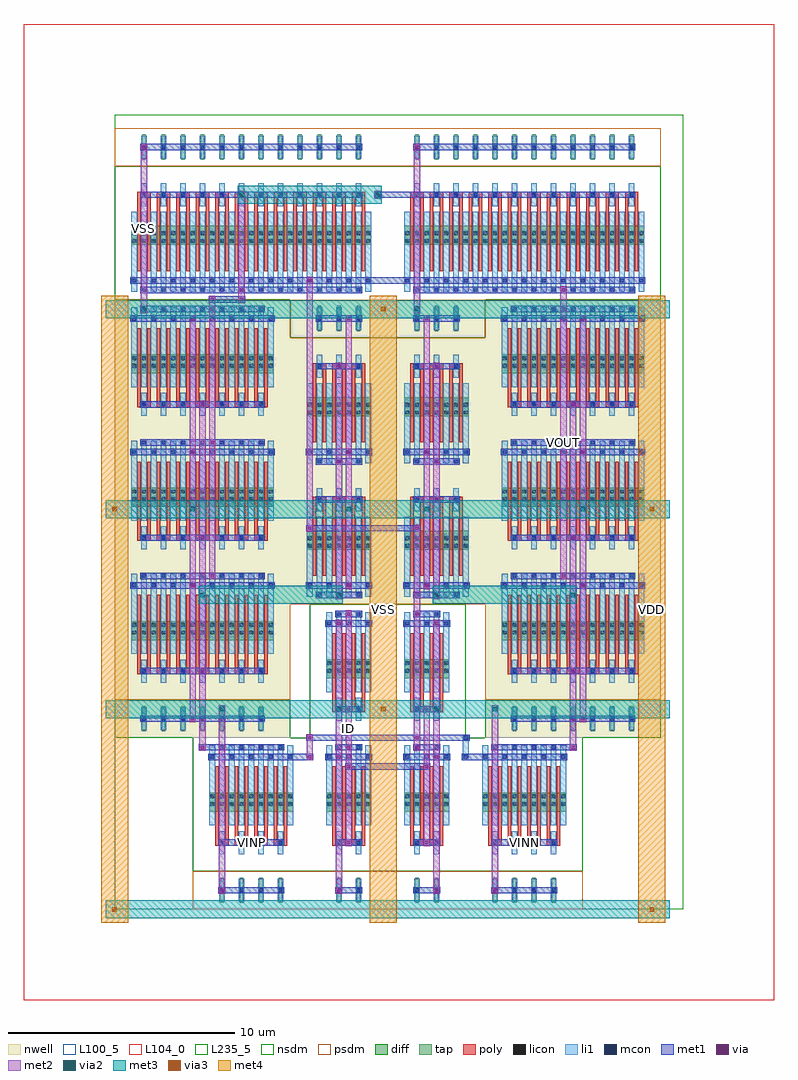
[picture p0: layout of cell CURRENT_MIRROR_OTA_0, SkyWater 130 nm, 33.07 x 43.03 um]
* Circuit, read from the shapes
.subckt CURRENT_MIRROR_OTA_0 ID VDD VINN VINP VOUT VSS
XM1 n1 n1 n2 VSS sky130_fd_pr__nfet_01v8 w=0.84 l=0.15 m=24
XM2 n3 VINP n2 VSS sky130_fd_pr__nfet_01v8 w=0.84 l=0.15 m=8
XM3 ID ID VSS VSS sky130_fd_pr__nfet_01v8 w=0.84 l=0.15 m=8
XM4 n2 ID VSS VSS sky130_fd_pr__nfet_01v8 w=0.84 l=0.15 m=8
XM5 VOUT n1 n2 VSS sky130_fd_pr__nfet_01v8 w=0.84 l=0.15 m=24
XM6 n4 VINN n2 VSS sky130_fd_pr__nfet_01v8 w=0.84 l=0.15 m=8
XM7 n1 n3 VDD VDD sky130_fd_pr__pfet_01v8 w=0.84 l=0.15 m=42
XM8 n3 n3 VDD VDD sky130_fd_pr__pfet_01v8 w=0.84 l=0.15 m=12
XM9 n4 n4 VDD VDD sky130_fd_pr__pfet_01v8 w=0.84 l=0.15 m=12
XM10 VOUT n4 VDD VDD sky130_fd_pr__pfet_01v8 w=0.84 l=0.15 m=42
.ends

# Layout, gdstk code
from math import pi, radians
import gdstk
lib = gdstk.Library(unit=1e-6, precision=1e-09)
def R(c, l, rs):  # rectangles x0, y0, x1, y1
    for r in rs: c.add(gdstk.rectangle(r[:2], r[2:], *l))
def A(c, l, x, y, w, h, nx, ny, dx, dy):  # array of equal rectangles
    R(c, l, [(x+i*dx, y+j*dy, x+i*dx+w, y+j*dy+h) for i in range(nx) for j in range(ny)])
def P(c, l, *ps):  # polygons
    for p in ps: c.add(gdstk.Polygon(p, *l))
nwell = (64, 20)
diff = (65, 20)
tap = (65, 44)
poly = (66, 20)
licon = (66, 44)
li1 = (67, 20)
mcon = (67, 44)
met1 = (68, 20)
via = (68, 44)
met2 = (69, 20)
via2 = (69, 44)
met3 = (70, 20)
via3 = (70, 44)
met4 = (71, 20)
nsdm = (93, 44)
psdm = (94, 20)
L100_5 = (100, 5)
L104_0 = (104, 0)
L235_5 = (235, 5)

dcl_nmos_s_47956387_x2_y = lib.new_cell('DCL_NMOS_S_47956387_X2_Y2_1725376080')
R(dcl_nmos_s_47956387_x2_y, diff, [(0.735,2.415,2.705,3.255), (0.735,8.295,2.705,9.135)])
R(dcl_nmos_s_47956387_x2_y, tap, [(1.205,12.04,1.375,13.16), (2.065,12.04,2.235,13.16)])
A(dcl_nmos_s_47956387_x2_y, poly, 1, 1.26, 0.15, 3.36, 4, 2, 0.43, 5.88)
R(dcl_nmos_s_47956387_x2_y, poly, [(1,4.485,1.58,4.755), (1.86,4.485,2.44,4.755), (1,10.365,1.58,10.635), (1.86,10.365,2.44,10.635)])
A(dcl_nmos_s_47956387_x2_y, licon, 0.775, 2.495, 0.17, 0.17, 3, 2, 0.43, 0.34)
A(dcl_nmos_s_47956387_x2_y, licon, 1.635, 2.495, 0.17, 0.17, 3, 2, 0.43, 0.34)
A(dcl_nmos_s_47956387_x2_y, licon, 0.775, 8.375, 0.17, 0.17, 3, 2, 0.43, 0.34)
A(dcl_nmos_s_47956387_x2_y, licon, 1.635, 8.375, 0.17, 0.17, 3, 2, 0.43, 0.34)
R(dcl_nmos_s_47956387_x2_y, licon, [(1.205,4.535,1.375,4.705), (2.065,4.535,2.235,4.705), (1.205,10.415,1.375,10.585), (2.065,10.415,2.235,10.585), (1.205,12.515,1.375,12.685), (1.205,12.515,1.375,12.685), (2.065,12.515,2.235,12.685), (2.065,12.515,2.235,12.685)])
A(dcl_nmos_s_47956387_x2_y, li1, 0.735, 0.335, 0.25, 3.53, 5, 2, 0.43, 5.88)
R(dcl_nmos_s_47956387_x2_y, li1, [(1.165,4.115,1.415,5.125), (2.025,4.115,2.275,5.125), (1.165,9.995,1.415,11.005), (2.025,9.995,2.275,11.005), (1.165,12.095,1.415,13.105), (2.025,12.095,2.275,13.105)])
A(dcl_nmos_s_47956387_x2_y, mcon, 0.775, 0.755, 0.17, 0.17, 3, 2, 0.86, 5.88)
R(dcl_nmos_s_47956387_x2_y, mcon, [(1.205,0.335,1.375,0.505), (2.065,0.335,2.235,0.505), (1.205,4.535,1.375,4.705), (2.065,4.535,2.235,4.705), (1.205,6.215,1.375,6.385), (2.065,6.215,2.235,6.385), (1.205,10.415,1.375,10.585), (2.065,10.415,2.235,10.585), (1.205,12.515,1.375,12.685), (2.065,12.515,2.235,12.685)])
R(dcl_nmos_s_47956387_x2_y, met1, [(1.12,0.28,2.32,0.56), (0.69,0.7,2.75,0.98), (1.12,4.48,2.32,4.76), (1.12,6.16,2.32,6.44), (0.69,6.58,2.75,6.86), (1.12,10.36,2.32,10.64), (1.12,12.46,2.32,12.74)])
A(dcl_nmos_s_47956387_x2_y, via, 2.075, 0.765, 0.15, 0.15, 1, 3, 0, 5.88)
R(dcl_nmos_s_47956387_x2_y, via, [(1.645,0.345,1.795,0.495), (1.645,4.545,1.795,4.695), (1.645,6.225,1.795,6.375), (1.645,10.425,1.795,10.575)])
R(dcl_nmos_s_47956387_x2_y, met2, [(1.58,0.26,1.86,10.66), (2.01,0.68,2.29,12.76)])
R(dcl_nmos_s_47956387_x2_y, nsdm, [(0,0,3.44,11.76)])
R(dcl_nmos_s_47956387_x2_y, psdm, [(0,11.76,3.44,13.44)])
R(dcl_nmos_s_47956387_x2_y, L100_5, [(0,0,3.44,13.44)])

dcl_pmos_s_40212493_x3_y = lib.new_cell('DCL_PMOS_S_40212493_X3_Y2_1725376081')
R(dcl_pmos_s_40212493_x3_y, nwell, [(0,0,4.3,13.44)])
R(dcl_pmos_s_40212493_x3_y, diff, [(0.735,2.415,3.565,3.255), (0.735,8.295,3.565,9.135)])
A(dcl_pmos_s_40212493_x3_y, tap, 1.205, 12.04, 0.17, 1.12, 3, 1, 0.86, 0)
A(dcl_pmos_s_40212493_x3_y, poly, 1, 1.26, 0.15, 3.36, 6, 2, 0.43, 5.88)
A(dcl_pmos_s_40212493_x3_y, poly, 1, 4.485, 0.58, 0.27, 3, 2, 0.86, 5.88)
A(dcl_pmos_s_40212493_x3_y, licon, 0.775, 2.495, 0.17, 0.17, 3, 2, 0.43, 0.34)
A(dcl_pmos_s_40212493_x3_y, licon, 1.635, 2.495, 0.17, 0.17, 3, 2, 0.43, 0.34)
A(dcl_pmos_s_40212493_x3_y, licon, 2.495, 2.495, 0.17, 0.17, 3, 2, 0.43, 0.34)
A(dcl_pmos_s_40212493_x3_y, licon, 1.205, 4.535, 0.17, 0.17, 3, 2, 0.86, 5.88)
A(dcl_pmos_s_40212493_x3_y, licon, 0.775, 8.375, 0.17, 0.17, 3, 2, 0.43, 0.34)
A(dcl_pmos_s_40212493_x3_y, licon, 1.635, 8.375, 0.17, 0.17, 3, 2, 0.43, 0.34)
A(dcl_pmos_s_40212493_x3_y, licon, 2.495, 8.375, 0.17, 0.17, 3, 2, 0.43, 0.34)
R(dcl_pmos_s_40212493_x3_y, licon, [(1.205,12.515,1.375,12.685), (1.205,12.515,1.375,12.685), (2.065,12.515,2.235,12.685), (2.065,12.515,2.235,12.685), (2.925,12.515,3.095,12.685), (2.925,12.515,3.095,12.685)])
A(dcl_pmos_s_40212493_x3_y, li1, 0.735, 0.335, 0.25, 3.53, 7, 2, 0.43, 5.88)
A(dcl_pmos_s_40212493_x3_y, li1, 1.165, 4.115, 0.25, 1.01, 3, 2, 0.86, 5.88)
A(dcl_pmos_s_40212493_x3_y, li1, 1.165, 12.095, 0.25, 1.01, 3, 1, 0.86, 0)
A(dcl_pmos_s_40212493_x3_y, mcon, 1.205, 0.335, 0.17, 0.17, 3, 2, 0.86, 4.2)
A(dcl_pmos_s_40212493_x3_y, mcon, 0.775, 0.755, 0.17, 0.17, 4, 2, 0.86, 5.88)
A(dcl_pmos_s_40212493_x3_y, mcon, 1.205, 6.215, 0.17, 0.17, 3, 2, 0.86, 4.2)
A(dcl_pmos_s_40212493_x3_y, mcon, 1.205, 12.515, 0.17, 0.17, 3, 1, 0.86, 0)
R(dcl_pmos_s_40212493_x3_y, met1, [(1.12,0.28,3.18,0.56), (0.69,0.7,3.61,0.98), (1.12,4.48,3.18,4.76), (1.12,6.16,3.18,6.44), (0.69,6.58,3.61,6.86), (1.12,10.36,3.18,10.64), (1.12,12.46,3.18,12.74)])
A(dcl_pmos_s_40212493_x3_y, via, 2.505, 0.765, 0.15, 0.15, 1, 3, 0, 5.88)
R(dcl_pmos_s_40212493_x3_y, via, [(2.075,0.345,2.225,0.495), (2.075,4.545,2.225,4.695), (2.075,6.225,2.225,6.375), (2.075,10.425,2.225,10.575)])
R(dcl_pmos_s_40212493_x3_y, met2, [(2.01,0.26,2.29,10.66), (2.44,0.68,2.72,12.76)])
R(dcl_pmos_s_40212493_x3_y, nsdm, [(0,11.76,4.3,13.44)])
R(dcl_pmos_s_40212493_x3_y, psdm, [(0,0,4.3,11.76)])
R(dcl_pmos_s_40212493_x3_y, L100_5, [(0,0,4.3,13.44)])

nmos_s_18635307_x2_y2_17 = lib.new_cell('NMOS_S_18635307_X2_Y2_1725376084')
R(nmos_s_18635307_x2_y2_17, diff, [(0.735,2.415,2.705,3.255), (0.735,8.295,2.705,9.135)])
R(nmos_s_18635307_x2_y2_17, tap, [(1.205,12.04,1.375,13.16), (2.065,12.04,2.235,13.16)])
A(nmos_s_18635307_x2_y2_17, poly, 1, 1.26, 0.15, 3.36, 4, 2, 0.43, 5.88)
R(nmos_s_18635307_x2_y2_17, poly, [(1,4.485,1.58,4.755), (1.86,4.485,2.44,4.755), (1,10.365,1.58,10.635), (1.86,10.365,2.44,10.635)])
A(nmos_s_18635307_x2_y2_17, licon, 0.775, 2.495, 0.17, 0.17, 3, 2, 0.43, 0.34)
A(nmos_s_18635307_x2_y2_17, licon, 1.635, 2.495, 0.17, 0.17, 3, 2, 0.43, 0.34)
A(nmos_s_18635307_x2_y2_17, licon, 0.775, 8.375, 0.17, 0.17, 3, 2, 0.43, 0.34)
A(nmos_s_18635307_x2_y2_17, licon, 1.635, 8.375, 0.17, 0.17, 3, 2, 0.43, 0.34)
R(nmos_s_18635307_x2_y2_17, licon, [(1.205,4.535,1.375,4.705), (2.065,4.535,2.235,4.705), (1.205,10.415,1.375,10.585), (2.065,10.415,2.235,10.585), (1.205,12.515,1.375,12.685), (1.205,12.515,1.375,12.685), (2.065,12.515,2.235,12.685), (2.065,12.515,2.235,12.685)])
A(nmos_s_18635307_x2_y2_17, li1, 0.735, 0.335, 0.25, 3.53, 5, 2, 0.43, 5.88)
R(nmos_s_18635307_x2_y2_17, li1, [(1.165,4.115,1.415,5.125), (2.025,4.115,2.275,5.125), (1.165,9.995,1.415,11.005), (2.025,9.995,2.275,11.005), (1.165,12.095,1.415,13.105), (2.025,12.095,2.275,13.105)])
A(nmos_s_18635307_x2_y2_17, mcon, 0.775, 0.755, 0.17, 0.17, 3, 2, 0.86, 5.88)
R(nmos_s_18635307_x2_y2_17, mcon, [(1.205,0.335,1.375,0.505), (2.065,0.335,2.235,0.505), (1.205,4.535,1.375,4.705), (2.065,4.535,2.235,4.705), (1.205,6.215,1.375,6.385), (2.065,6.215,2.235,6.385), (1.205,10.415,1.375,10.585), (2.065,10.415,2.235,10.585), (1.205,12.515,1.375,12.685), (2.065,12.515,2.235,12.685)])
R(nmos_s_18635307_x2_y2_17, met1, [(1.12,0.28,2.32,0.56), (0.69,0.7,2.75,0.98), (1.12,4.48,2.32,4.76), (1.12,6.16,2.32,6.44), (0.69,6.58,2.75,6.86), (1.12,10.36,2.32,10.64), (1.12,12.46,2.32,12.74)])
A(nmos_s_18635307_x2_y2_17, via, 2.075, 0.765, 0.15, 0.15, 1, 3, 0, 5.88)
R(nmos_s_18635307_x2_y2_17, via, [(1.215,0.345,1.365,0.495), (1.645,4.545,1.795,4.695), (1.215,6.225,1.365,6.375), (1.645,10.425,1.795,10.575)])
R(nmos_s_18635307_x2_y2_17, met2, [(1.15,0.26,1.43,6.46), (2.01,0.68,2.29,12.76), (1.58,4.46,1.86,10.66)])
R(nmos_s_18635307_x2_y2_17, nsdm, [(0,0,3.44,11.76)])
R(nmos_s_18635307_x2_y2_17, psdm, [(0,11.76,3.44,13.44)])
R(nmos_s_18635307_x2_y2_17, L100_5, [(0,0,3.44,13.44)])

pmos_s_18257507_x7_y3_17 = lib.new_cell('PMOS_S_18257507_X7_Y3_1725376085')
R(pmos_s_18257507_x7_y3_17, nwell, [(0,0,7.74,19.32)])
A(pmos_s_18257507_x7_y3_17, diff, 0.735, 2.415, 6.27, 0.84, 1, 3, 0, 5.88)
A(pmos_s_18257507_x7_y3_17, tap, 1.205, 17.92, 0.17, 1.12, 7, 1, 0.86, 0)
A(pmos_s_18257507_x7_y3_17, poly, 1, 1.26, 0.15, 3.36, 14, 3, 0.43, 5.88)
A(pmos_s_18257507_x7_y3_17, poly, 1, 4.485, 0.58, 0.27, 7, 3, 0.86, 5.88)
A(pmos_s_18257507_x7_y3_17, licon, 0.775, 2.495, 0.17, 0.17, 3, 2, 0.43, 0.34)
A(pmos_s_18257507_x7_y3_17, licon, 1.635, 2.495, 0.17, 0.17, 3, 2, 0.43, 0.34)
A(pmos_s_18257507_x7_y3_17, licon, 2.495, 2.495, 0.17, 0.17, 3, 2, 0.43, 0.34)
A(pmos_s_18257507_x7_y3_17, licon, 3.355, 2.495, 0.17, 0.17, 3, 2, 0.43, 0.34)
A(pmos_s_18257507_x7_y3_17, licon, 4.215, 2.495, 0.17, 0.17, 3, 2, 0.43, 0.34)
A(pmos_s_18257507_x7_y3_17, licon, 5.075, 2.495, 0.17, 0.17, 3, 2, 0.43, 0.34)
A(pmos_s_18257507_x7_y3_17, licon, 5.935, 2.495, 0.17, 0.17, 3, 2, 0.43, 0.34)
A(pmos_s_18257507_x7_y3_17, licon, 1.205, 4.535, 0.17, 0.17, 7, 3, 0.86, 5.88)
A(pmos_s_18257507_x7_y3_17, licon, 0.775, 8.375, 0.17, 0.17, 3, 2, 0.43, 0.34)
A(pmos_s_18257507_x7_y3_17, licon, 1.635, 8.375, 0.17, 0.17, 3, 2, 0.43, 0.34)
A(pmos_s_18257507_x7_y3_17, licon, 2.495, 8.375, 0.17, 0.17, 3, 2, 0.43, 0.34)
A(pmos_s_18257507_x7_y3_17, licon, 3.355, 8.375, 0.17, 0.17, 3, 2, 0.43, 0.34)
A(pmos_s_18257507_x7_y3_17, licon, 4.215, 8.375, 0.17, 0.17, 3, 2, 0.43, 0.34)
A(pmos_s_18257507_x7_y3_17, licon, 5.075, 8.375, 0.17, 0.17, 3, 2, 0.43, 0.34)
A(pmos_s_18257507_x7_y3_17, licon, 5.935, 8.375, 0.17, 0.17, 3, 2, 0.43, 0.34)
A(pmos_s_18257507_x7_y3_17, licon, 0.775, 14.255, 0.17, 0.17, 3, 2, 0.43, 0.34)
A(pmos_s_18257507_x7_y3_17, licon, 1.635, 14.255, 0.17, 0.17, 3, 2, 0.43, 0.34)
A(pmos_s_18257507_x7_y3_17, licon, 2.495, 14.255, 0.17, 0.17, 3, 2, 0.43, 0.34)
A(pmos_s_18257507_x7_y3_17, licon, 3.355, 14.255, 0.17, 0.17, 3, 2, 0.43, 0.34)
A(pmos_s_18257507_x7_y3_17, licon, 4.215, 14.255, 0.17, 0.17, 3, 2, 0.43, 0.34)
A(pmos_s_18257507_x7_y3_17, licon, 5.075, 14.255, 0.17, 0.17, 3, 2, 0.43, 0.34)
A(pmos_s_18257507_x7_y3_17, licon, 5.935, 14.255, 0.17, 0.17, 3, 2, 0.43, 0.34)
R(pmos_s_18257507_x7_y3_17, licon, [(1.205,18.395,1.375,18.565), (1.205,18.395,1.375,18.565), (1.205,18.395,1.375,18.565), (2.065,18.395,2.235,18.565), (2.065,18.395,2.235,18.565), (2.065,18.395,2.235,18.565), (2.925,18.395,3.095,18.565), (2.925,18.395,3.095,18.565), (2.925,18.395,3.095,18.565), (3.785,18.395,3.955,18.565), (3.785,18.395,3.955,18.565), (3.785,18.395,3.955,18.565), (4.645,18.395,4.815,18.565), (4.645,18.395,4.815,18.565), (4.645,18.395,4.815,18.565), (5.505,18.395,5.675,18.565), (5.505,18.395,5.675,18.565), (5.505,18.395,5.675,18.565), (6.365,18.395,6.535,18.565), (6.365,18.395,6.535,18.565), (6.365,18.395,6.535,18.565)])
A(pmos_s_18257507_x7_y3_17, li1, 0.735, 0.335, 0.25, 3.53, 15, 3, 0.43, 5.88)
A(pmos_s_18257507_x7_y3_17, li1, 1.165, 4.115, 0.25, 1.01, 7, 3, 0.86, 5.88)
A(pmos_s_18257507_x7_y3_17, li1, 1.165, 17.975, 0.25, 1.01, 7, 1, 0.86, 0)
A(pmos_s_18257507_x7_y3_17, mcon, 1.205, 0.335, 0.17, 0.17, 7, 2, 0.86, 4.2)
A(pmos_s_18257507_x7_y3_17, mcon, 0.775, 0.755, 0.17, 0.17, 8, 3, 0.86, 5.88)
A(pmos_s_18257507_x7_y3_17, mcon, 1.205, 6.215, 0.17, 0.17, 7, 2, 0.86, 4.2)
A(pmos_s_18257507_x7_y3_17, mcon, 1.205, 12.095, 0.17, 0.17, 7, 2, 0.86, 4.2)
A(pmos_s_18257507_x7_y3_17, mcon, 1.205, 18.395, 0.17, 0.17, 7, 1, 0.86, 0)
A(pmos_s_18257507_x7_y3_17, met1, 0.69, 0.7, 6.36, 0.28, 1, 3, 0, 5.88)
R(pmos_s_18257507_x7_y3_17, met1, [(1.12,0.28,6.62,0.56), (1.12,4.48,6.62,4.76), (1.12,6.16,6.62,6.44), (1.12,10.36,6.62,10.64), (1.12,12.04,6.62,12.32), (1.12,16.24,6.62,16.52), (1.12,18.34,6.62,18.62)])
A(pmos_s_18257507_x7_y3_17, via, 3.365, 0.345, 0.15, 0.15, 1, 3, 0, 5.88)
A(pmos_s_18257507_x7_y3_17, via, 4.225, 0.765, 0.15, 0.15, 1, 4, 0, 5.88)
A(pmos_s_18257507_x7_y3_17, via, 3.795, 4.545, 0.15, 0.15, 1, 3, 0, 5.88)
R(pmos_s_18257507_x7_y3_17, met2, [(3.3,0.26,3.58,12.34), (4.16,0.68,4.44,18.64), (3.73,4.46,4.01,16.54)])
R(pmos_s_18257507_x7_y3_17, nsdm, [(0,17.64,7.74,19.32)])
R(pmos_s_18257507_x7_y3_17, psdm, [(0,0,7.74,17.64)])
R(pmos_s_18257507_x7_y3_17, L100_5, [(0,0,7.74,19.32)])

dcl_nmos_10568373_x12_y1 = lib.new_cell('DCL_NMOS_10568373_X12_Y1_1725376079')
R(dcl_nmos_10568373_x12_y1, diff, [(0.735,2.415,11.305,3.255)])
A(dcl_nmos_10568373_x12_y1, tap, 1.205, 6.16, 0.17, 1.12, 12, 1, 0.86, 0)
A(dcl_nmos_10568373_x12_y1, poly, 1, 1.26, 0.15, 3.36, 24, 1, 0.43, 0)
A(dcl_nmos_10568373_x12_y1, poly, 1, 4.485, 0.58, 0.27, 12, 1, 0.86, 0)
A(dcl_nmos_10568373_x12_y1, licon, 0.775, 2.495, 0.17, 0.17, 3, 2, 0.43, 0.34)
A(dcl_nmos_10568373_x12_y1, licon, 1.635, 2.495, 0.17, 0.17, 3, 2, 0.43, 0.34)
A(dcl_nmos_10568373_x12_y1, licon, 2.495, 2.495, 0.17, 0.17, 3, 2, 0.43, 0.34)
A(dcl_nmos_10568373_x12_y1, licon, 3.355, 2.495, 0.17, 0.17, 3, 2, 0.43, 0.34)
A(dcl_nmos_10568373_x12_y1, licon, 4.215, 2.495, 0.17, 0.17, 3, 2, 0.43, 0.34)
A(dcl_nmos_10568373_x12_y1, licon, 5.075, 2.495, 0.17, 0.17, 3, 2, 0.43, 0.34)
A(dcl_nmos_10568373_x12_y1, licon, 5.935, 2.495, 0.17, 0.17, 3, 2, 0.43, 0.34)
A(dcl_nmos_10568373_x12_y1, licon, 6.795, 2.495, 0.17, 0.17, 3, 2, 0.43, 0.34)
A(dcl_nmos_10568373_x12_y1, licon, 7.655, 2.495, 0.17, 0.17, 3, 2, 0.43, 0.34)
A(dcl_nmos_10568373_x12_y1, licon, 8.515, 2.495, 0.17, 0.17, 3, 2, 0.43, 0.34)
A(dcl_nmos_10568373_x12_y1, licon, 9.375, 2.495, 0.17, 0.17, 3, 2, 0.43, 0.34)
A(dcl_nmos_10568373_x12_y1, licon, 10.235, 2.495, 0.17, 0.17, 3, 2, 0.43, 0.34)
A(dcl_nmos_10568373_x12_y1, licon, 1.205, 4.535, 0.17, 0.17, 12, 2, 0.86, 2.1)
A(dcl_nmos_10568373_x12_y1, li1, 0.735, 0.335, 0.25, 3.53, 25, 1, 0.43, 0)
A(dcl_nmos_10568373_x12_y1, li1, 1.165, 4.115, 0.25, 1.01, 12, 2, 0.86, 2.1)
A(dcl_nmos_10568373_x12_y1, mcon, 1.205, 0.335, 0.17, 0.17, 12, 2, 0.86, 4.2)
A(dcl_nmos_10568373_x12_y1, mcon, 0.775, 0.755, 0.17, 0.17, 13, 1, 0.86, 0)
A(dcl_nmos_10568373_x12_y1, mcon, 1.205, 6.635, 0.17, 0.17, 12, 1, 0.86, 0)
R(dcl_nmos_10568373_x12_y1, met1, [(1.12,0.28,10.92,0.56), (0.69,0.7,11.35,0.98), (1.12,4.48,10.92,4.76), (1.12,6.58,10.92,6.86)])
R(dcl_nmos_10568373_x12_y1, via, [(5.515,0.345,5.665,0.495), (5.515,4.545,5.665,4.695)])
R(dcl_nmos_10568373_x12_y1, met2, [(5.45,0.26,5.73,4.78)])
R(dcl_nmos_10568373_x12_y1, nsdm, [(0,0,12.04,5.88)])
R(dcl_nmos_10568373_x12_y1, psdm, [(0,5.88,12.04,7.56)])
R(dcl_nmos_10568373_x12_y1, L100_5, [(0,0,12.04,7.56)])

nmos_4t_40251920_x4_y1_1 = lib.new_cell('NMOS_4T_40251920_X4_Y1_1725376082')
R(nmos_4t_40251920_x4_y1_1, diff, [(0.735,2.415,4.425,3.255)])
A(nmos_4t_40251920_x4_y1_1, tap, 1.205, 6.16, 0.17, 1.12, 4, 1, 0.86, 0)
A(nmos_4t_40251920_x4_y1_1, poly, 1, 1.26, 0.15, 3.36, 8, 1, 0.43, 0)
A(nmos_4t_40251920_x4_y1_1, poly, 1, 4.485, 0.58, 0.27, 4, 1, 0.86, 0)
A(nmos_4t_40251920_x4_y1_1, licon, 0.775, 2.495, 0.17, 0.17, 3, 2, 0.43, 0.34)
A(nmos_4t_40251920_x4_y1_1, licon, 1.635, 2.495, 0.17, 0.17, 3, 2, 0.43, 0.34)
A(nmos_4t_40251920_x4_y1_1, licon, 2.495, 2.495, 0.17, 0.17, 3, 2, 0.43, 0.34)
A(nmos_4t_40251920_x4_y1_1, licon, 3.355, 2.495, 0.17, 0.17, 3, 2, 0.43, 0.34)
A(nmos_4t_40251920_x4_y1_1, licon, 1.205, 4.535, 0.17, 0.17, 4, 2, 0.86, 2.1)
A(nmos_4t_40251920_x4_y1_1, li1, 0.735, 0.335, 0.25, 3.53, 9, 1, 0.43, 0)
A(nmos_4t_40251920_x4_y1_1, li1, 1.165, 4.115, 0.25, 1.01, 4, 2, 0.86, 2.1)
A(nmos_4t_40251920_x4_y1_1, mcon, 1.205, 0.335, 0.17, 0.17, 4, 2, 0.86, 4.2)
A(nmos_4t_40251920_x4_y1_1, mcon, 0.775, 0.755, 0.17, 0.17, 5, 1, 0.86, 0)
A(nmos_4t_40251920_x4_y1_1, mcon, 1.205, 6.635, 0.17, 0.17, 4, 1, 0.86, 0)
R(nmos_4t_40251920_x4_y1_1, met1, [(1.12,0.28,4.04,0.56), (0.69,0.7,4.47,0.98), (1.12,4.48,4.04,4.76), (1.12,6.58,4.04,6.86)])
R(nmos_4t_40251920_x4_y1_1, nsdm, [(0,0,5.16,5.88)])
R(nmos_4t_40251920_x4_y1_1, psdm, [(0,5.88,5.16,7.56)])
R(nmos_4t_40251920_x4_y1_1, L100_5, [(0,0,5.16,7.56)])

nmos_4t_8992804_x12_y1_1 = lib.new_cell('NMOS_4T_8992804_X12_Y1_1725376083')
R(nmos_4t_8992804_x12_y1_1, diff, [(0.735,2.415,11.305,3.255)])
A(nmos_4t_8992804_x12_y1_1, tap, 1.205, 6.16, 0.17, 1.12, 12, 1, 0.86, 0)
A(nmos_4t_8992804_x12_y1_1, poly, 1, 1.26, 0.15, 3.36, 24, 1, 0.43, 0)
A(nmos_4t_8992804_x12_y1_1, poly, 1, 4.485, 0.58, 0.27, 12, 1, 0.86, 0)
A(nmos_4t_8992804_x12_y1_1, licon, 0.775, 2.495, 0.17, 0.17, 3, 2, 0.43, 0.34)
A(nmos_4t_8992804_x12_y1_1, licon, 1.635, 2.495, 0.17, 0.17, 3, 2, 0.43, 0.34)
A(nmos_4t_8992804_x12_y1_1, licon, 2.495, 2.495, 0.17, 0.17, 3, 2, 0.43, 0.34)
A(nmos_4t_8992804_x12_y1_1, licon, 3.355, 2.495, 0.17, 0.17, 3, 2, 0.43, 0.34)
A(nmos_4t_8992804_x12_y1_1, licon, 4.215, 2.495, 0.17, 0.17, 3, 2, 0.43, 0.34)
A(nmos_4t_8992804_x12_y1_1, licon, 5.075, 2.495, 0.17, 0.17, 3, 2, 0.43, 0.34)
A(nmos_4t_8992804_x12_y1_1, licon, 5.935, 2.495, 0.17, 0.17, 3, 2, 0.43, 0.34)
A(nmos_4t_8992804_x12_y1_1, licon, 6.795, 2.495, 0.17, 0.17, 3, 2, 0.43, 0.34)
A(nmos_4t_8992804_x12_y1_1, licon, 7.655, 2.495, 0.17, 0.17, 3, 2, 0.43, 0.34)
A(nmos_4t_8992804_x12_y1_1, licon, 8.515, 2.495, 0.17, 0.17, 3, 2, 0.43, 0.34)
A(nmos_4t_8992804_x12_y1_1, licon, 9.375, 2.495, 0.17, 0.17, 3, 2, 0.43, 0.34)
A(nmos_4t_8992804_x12_y1_1, licon, 10.235, 2.495, 0.17, 0.17, 3, 2, 0.43, 0.34)
A(nmos_4t_8992804_x12_y1_1, licon, 1.205, 4.535, 0.17, 0.17, 12, 2, 0.86, 2.1)
A(nmos_4t_8992804_x12_y1_1, li1, 0.735, 0.335, 0.25, 3.53, 25, 1, 0.43, 0)
A(nmos_4t_8992804_x12_y1_1, li1, 1.165, 4.115, 0.25, 1.01, 12, 2, 0.86, 2.1)
A(nmos_4t_8992804_x12_y1_1, mcon, 1.205, 0.335, 0.17, 0.17, 12, 2, 0.86, 4.2)
A(nmos_4t_8992804_x12_y1_1, mcon, 0.775, 0.755, 0.17, 0.17, 13, 1, 0.86, 0)
A(nmos_4t_8992804_x12_y1_1, mcon, 1.205, 6.635, 0.17, 0.17, 12, 1, 0.86, 0)
R(nmos_4t_8992804_x12_y1_1, met1, [(1.12,0.28,10.92,0.56), (0.69,0.7,11.35,0.98), (1.12,4.48,10.92,4.76), (1.12,6.58,10.92,6.86)])
R(nmos_4t_8992804_x12_y1_1, nsdm, [(0,0,12.04,5.88)])
R(nmos_4t_8992804_x12_y1_1, psdm, [(0,5.88,12.04,7.56)])
R(nmos_4t_8992804_x12_y1_1, L100_5, [(0,0,12.04,7.56)])

current_mirror_ota_0 = lib.new_cell('CURRENT_MIRROR_OTA_0')
R(current_mirror_ota_0, li1, [(15.355,6.635,15.605,6.805), (15.355,6.635,15.605,6.805), (15.355,6.635,15.605,6.805), (15.355,6.635,15.605,6.805), (15.355,6.635,15.605,6.805), (15.355,6.635,15.605,6.805), (15.355,6.72,15.605,7.56), (15.355,7.475,15.605,7.645), (15.355,7.475,15.605,7.645), (15.355,7.475,15.605,7.645), (15.355,7.475,15.605,7.645), (15.355,7.475,15.605,7.645), (15.355,7.475,15.605,7.645)])
R(current_mirror_ota_0, mcon, [(15.395,6.635,15.565,6.805), (15.395,6.635,15.565,6.805), (15.395,6.635,15.565,6.805), (15.395,6.635,15.565,6.805), (15.395,6.635,15.565,6.805), (15.395,6.635,15.565,6.805), (15.395,7.475,15.565,7.645), (15.395,7.475,15.565,7.645), (15.395,7.475,15.565,7.645), (15.395,7.475,15.565,7.645), (15.395,7.475,15.565,7.645), (15.395,7.475,15.565,7.645)])
R(current_mirror_ota_0, met1, [(4.57,0.7,4.89,0.98), (4.57,0.7,4.89,0.98), (4.57,0.7,4.89,0.98), (16.61,0.7,16.93,0.98), (16.61,0.7,16.93,0.98), (16.61,0.7,16.93,0.98), (16.61,0.7,16.93,0.98), (10.16,6.16,10.48,6.44), (10.16,6.16,10.48,6.44), (10.32,6.16,13.76,6.44), (13.6,6.16,13.92,6.44), (13.6,6.16,13.92,6.44), (7.74,6.58,8.6,6.86), (8.44,6.58,8.76,6.86), (8.44,6.58,8.76,6.86), (8.44,6.58,8.76,6.86), (8.44,6.58,8.76,6.86), (8.44,6.58,8.76,6.86), (8.44,6.58,8.76,6.86), (8.44,6.58,8.76,6.86), (8.44,6.58,8.76,6.86), (15.31,6.58,15.65,6.86), (15.31,6.58,15.65,6.86), (15.31,6.58,15.65,6.86), (15.31,6.58,15.65,6.86), (15.31,6.58,15.65,6.86), (15.31,6.58,15.65,6.86), (15.48,6.58,16.34,6.86), (3.71,7,4.03,7.28), (3.71,7,4.03,7.28), (3.71,7,4.03,7.28), (3.71,7,4.03,7.28), (3.87,7,4.73,7.28), (19.35,7,20.21,7.28), (20.05,7,20.37,7.28), (20.05,7,20.37,7.28), (20.05,7,20.37,7.28), (20.05,7,20.37,7.28), (8.44,7.42,8.76,7.7), (8.44,7.42,8.76,7.7), (8.44,7.42,8.76,7.7), (8.44,7.42,8.76,7.7), (8.44,7.42,8.76,7.7), (8.44,7.42,8.76,7.7), (8.44,7.42,8.76,7.7), (8.44,7.42,8.76,7.7), (8.6,7.42,13.33,7.7), (13.17,7.42,13.49,7.7), (13.17,7.42,13.49,7.7), (13.17,7.42,13.49,7.7), (13.17,7.42,13.49,7.7), (13.17,7.42,13.49,7.7), (13.17,7.42,13.49,7.7), (13.17,7.42,13.49,7.7), (13.17,7.42,13.49,7.7), (13.33,7.42,15.48,7.7), (15.31,7.42,15.65,7.7), (15.31,7.42,15.65,7.7), (15.31,7.42,15.65,7.7), (15.31,7.42,15.65,7.7), (15.31,7.42,15.65,7.7), (15.31,7.42,15.65,7.7), (8.44,16.66,8.76,16.94), (8.44,16.66,8.76,16.94), (8.44,16.66,8.76,16.94), (8.44,16.66,8.76,16.94), (8.6,16.66,13.33,16.94), (13.17,16.66,13.49,16.94), (13.17,16.66,13.49,16.94), (13.17,16.66,13.49,16.94), (13.17,16.66,13.49,16.94), (4.14,26.74,4.46,27.02), (4.14,26.74,4.46,27.02), (4.14,26.74,4.46,27.02), (4.14,26.74,4.46,27.02), (4.3,26.74,5.59,27.02), (5.43,26.74,5.75,27.02), (5.43,26.74,5.75,27.02), (5.43,26.74,5.75,27.02), (5.43,26.74,5.75,27.02), (19.62,27.16,19.94,27.44), (19.62,27.16,19.94,27.44), (8.44,27.58,8.76,27.86), (8.44,27.58,8.76,27.86), (8.44,27.58,8.76,27.86), (8.44,27.58,8.76,27.86), (11.18,27.58,12.9,27.86), (11.45,31.36,11.77,31.64), (11.61,31.36,13.33,31.64), (1.13,33.46,1.45,33.74), (1.13,33.46,1.45,33.74), (1.13,33.46,1.45,33.74), (1.13,33.46,1.45,33.74), (1.13,33.46,1.45,33.74), (13.17,33.46,13.49,33.74), (13.17,33.46,13.49,33.74)])
P(current_mirror_ota_0, met1, [(0,0),(0,0),(0,0),(0,0)],
  [(0,0),(0,0),(0,0),(0,0)],
  [(0,0),(0,0),(0,0),(0,0)],
  [(0,0),(0,0),(0,0),(0,0)],
  [(0,0),(0,0),(0,0),(0,0)],
  [(0,0),(0,0),(0,0),(0,0)],
  [(0,0),(0,0),(0,0),(0,0)],
  [(0,0),(0,0),(0,0),(0,0)],
  [(0,0),(0,0),(0,0),(0,0)],
  [(0,0),(0,0),(0,0),(0,0)],
  [(0,0),(0,0),(0,0),(0,0)],
  [(0,0),(0,0),(0,0),(0,0)],
  [(0,0),(0,0),(0,0),(0,0)],
  [(0,0),(0,0),(0,0),(0,0)],
  [(0,0),(0,0),(0,0),(0,0)],
  [(0,0),(0,0),(0,0),(0,0)])
R(current_mirror_ota_0, via, [(4.655,0.765,4.805,0.915), (4.655,0.765,4.805,0.915), (4.655,0.765,4.805,0.915), (16.695,0.765,16.845,0.915), (16.695,0.765,16.845,0.915), (16.695,0.765,16.845,0.915), (16.695,0.765,16.845,0.915), (10.245,6.225,10.395,6.375), (10.245,6.225,10.395,6.375), (13.685,6.225,13.835,6.375), (13.685,6.225,13.835,6.375), (8.525,6.645,8.675,6.795), (8.525,6.645,8.675,6.795), (8.525,6.645,8.675,6.795), (8.525,6.645,8.675,6.795), (8.525,6.645,8.675,6.795), (8.525,6.645,8.675,6.795), (8.525,6.645,8.675,6.795), (8.525,6.645,8.675,6.795), (3.795,7.065,3.945,7.215), (3.795,7.065,3.945,7.215), (3.795,7.065,3.945,7.215), (3.795,7.065,3.945,7.215), (20.135,7.065,20.285,7.215), (20.135,7.065,20.285,7.215), (20.135,7.065,20.285,7.215), (20.135,7.065,20.285,7.215), (8.525,7.485,8.675,7.635), (8.525,7.485,8.675,7.635), (8.525,7.485,8.675,7.635), (8.525,7.485,8.675,7.635), (8.525,7.485,8.675,7.635), (8.525,7.485,8.675,7.635), (8.525,7.485,8.675,7.635), (8.525,7.485,8.675,7.635), (13.255,7.485,13.405,7.635), (13.255,7.485,13.405,7.635), (13.255,7.485,13.405,7.635), (13.255,7.485,13.405,7.635), (13.255,7.485,13.405,7.635), (13.255,7.485,13.405,7.635), (13.255,7.485,13.405,7.635), (13.255,7.485,13.405,7.635), (8.525,16.725,8.675,16.875), (8.525,16.725,8.675,16.875), (8.525,16.725,8.675,16.875), (8.525,16.725,8.675,16.875), (13.255,16.725,13.405,16.875), (13.255,16.725,13.405,16.875), (13.255,16.725,13.405,16.875), (13.255,16.725,13.405,16.875), (4.225,26.805,4.375,26.955), (4.225,26.805,4.375,26.955), (4.225,26.805,4.375,26.955), (4.225,26.805,4.375,26.955), (5.515,26.805,5.665,26.955), (5.515,26.805,5.665,26.955), (5.515,26.805,5.665,26.955), (5.515,26.805,5.665,26.955), (19.705,27.225,19.855,27.375), (19.705,27.225,19.855,27.375), (8.525,27.645,8.675,27.795), (8.525,27.645,8.675,27.795), (8.525,27.645,8.675,27.795), (8.525,27.645,8.675,27.795), (11.535,31.425,11.685,31.575), (1.215,33.525,1.365,33.675), (1.215,33.525,1.365,33.675), (1.215,33.525,1.365,33.675), (1.215,33.525,1.365,33.675), (1.215,33.525,1.365,33.675), (13.255,33.525,13.405,33.675), (13.255,33.525,13.405,33.675)])
R(current_mirror_ota_0, met2, [(4.59,0.68,4.87,1), (4.59,0.68,4.87,1), (4.59,0.68,4.87,1), (16.63,0.68,16.91,1), (16.63,0.68,16.91,1), (16.63,0.68,16.91,1), (16.63,0.68,16.91,1), (4.59,0.84,4.87,8.82), (16.63,0.84,16.91,8.82), (10.18,6.14,10.46,6.46), (10.18,6.14,10.46,6.46), (13.62,6.14,13.9,6.46), (13.62,6.14,13.9,6.46), (8.46,6.56,8.74,6.88), (8.46,6.56,8.74,6.88), (8.46,6.56,8.74,6.88), (8.46,6.56,8.74,6.88), (8.46,6.56,8.74,6.88), (8.46,6.56,8.74,6.88), (8.46,6.56,8.74,6.88), (8.46,6.56,8.74,6.88), (8.46,6.72,8.74,7.56), (3.73,6.98,4.01,7.3), (3.73,6.98,4.01,7.3), (3.73,6.98,4.01,7.3), (3.73,6.98,4.01,7.3), (20.07,6.98,20.35,7.3), (20.07,6.98,20.35,7.3), (20.07,6.98,20.35,7.3), (20.07,6.98,20.35,7.3), (3.73,7.14,4.01,10.5), (20.07,7.14,20.35,10.5), (8.46,7.4,8.74,7.72), (8.46,7.4,8.74,7.72), (8.46,7.4,8.74,7.72), (8.46,7.4,8.74,7.72), (8.46,7.4,8.74,7.72), (8.46,7.4,8.74,7.72), (8.46,7.4,8.74,7.72), (8.46,7.4,8.74,7.72), (13.19,7.4,13.47,7.72), (13.19,7.4,13.47,7.72), (13.19,7.4,13.47,7.72), (13.19,7.4,13.47,7.72), (13.19,7.4,13.47,7.72), (13.19,7.4,13.47,7.72), (13.19,7.4,13.47,7.72), (13.19,7.4,13.47,7.72), (4.59,8.635,4.87,9.005), (4.59,8.635,4.87,9.005), (4.59,8.635,4.87,9.005), (9.75,8.635,10.03,9.005), (9.75,8.635,10.03,9.005), (9.75,8.635,10.03,9.005), (9.75,8.635,10.03,9.005), (9.75,8.635,10.03,9.005), (9.75,8.635,10.03,9.005), (9.75,8.635,10.03,9.005), (14.05,8.635,14.33,9.005), (14.05,8.635,14.33,9.005), (14.05,8.635,14.33,9.005), (14.05,8.635,14.33,9.005), (14.05,8.635,14.33,9.005), (14.05,8.635,14.33,9.005), (16.63,8.635,16.91,9.005), (16.63,8.635,16.91,9.005), (16.63,8.635,16.91,9.005), (16.63,8.635,16.91,9.005), (13.19,13.02,13.47,16.8), (3.73,13.675,4.01,14.045), (3.73,13.675,4.01,14.045), (9.75,13.675,10.03,14.045), (9.75,13.675,10.03,14.045), (14.05,13.675,14.33,14.045), (14.05,13.675,14.33,14.045), (20.07,13.675,20.35,14.045), (20.07,13.675,20.35,14.045), (8.46,16.64,8.74,16.96), (8.46,16.64,8.74,16.96), (8.46,16.64,8.74,16.96), (8.46,16.64,8.74,16.96), (13.19,16.64,13.47,16.96), (13.19,16.64,13.47,16.96), (13.19,16.64,13.47,16.96), (13.19,16.64,13.47,16.96), (8.46,16.8,8.74,27.72), (3.3,17.455,3.58,17.825), (3.3,17.455,3.58,17.825), (3.3,17.455,3.58,17.825), (10.18,17.455,10.46,17.825), (10.18,17.455,10.46,17.825), (10.18,17.455,10.46,17.825), (10.18,17.455,10.46,17.825), (13.62,17.455,13.9,17.825), (13.62,17.455,13.9,17.825), (13.62,17.455,13.9,17.825), (13.62,17.455,13.9,17.825), (13.62,17.455,13.9,17.825), (20.5,17.455,20.78,17.825), (20.5,17.455,20.78,17.825), (1.15,26.275,1.43,26.645), (1.15,26.275,1.43,26.645), (1.15,26.275,1.43,26.645), (1.15,26.275,1.43,26.645), (1.15,26.275,1.43,26.645), (13.19,26.275,13.47,26.645), (13.19,26.275,13.47,26.645), (1.15,26.46,1.43,33.6), (4.16,26.46,4.44,26.88), (13.19,26.46,13.47,33.6), (19.64,26.46,19.92,27.3), (4.16,26.72,4.44,27.04), (4.16,26.72,4.44,27.04), (4.16,26.72,4.44,27.04), (4.16,26.72,4.44,27.04), (5.45,26.72,5.73,27.04), (5.45,26.72,5.73,27.04), (5.45,26.72,5.73,27.04), (5.45,26.72,5.73,27.04), (5.45,26.88,5.73,27.3), (19.64,27.14,19.92,27.46), (19.64,27.14,19.92,27.46), (8.46,27.56,8.74,27.88), (8.46,27.56,8.74,27.88), (8.46,27.56,8.74,27.88), (8.46,27.56,8.74,27.88), (5.45,31.315,5.73,31.685), (5.45,31.315,5.73,31.685), (11.47,31.315,11.75,31.685), (11.47,31.34,11.75,31.66), (11.47,31.379,11.75,31.621), (1.15,33.44,1.43,33.76), (1.15,33.44,1.43,33.76), (1.15,33.44,1.43,33.76), (1.15,33.44,1.43,33.76), (1.15,33.44,1.43,33.76), (13.19,33.44,13.47,33.76), (13.19,33.44,13.47,33.76)])
P(current_mirror_ota_0, met2, [(0,0),(0,0),(0,0),(0,0)],
  [(0,0),(0,0),(0,0),(0,0)],
  [(0,0),(0,0),(0,0),(0,0)],
  [(0,0),(0,0),(0,0),(0,0)],
  [(0,0),(0,0),(0,0),(0,0)],
  [(0,0),(0,0),(0,0),(0,0)],
  [(0,0),(0,0),(0,0),(0,0)],
  [(0,0),(0,0),(0,0),(0,0)],
  [(0,0),(0,0),(0,0),(0,0)],
  [(0,0),(0,0),(0,0),(0,0)],
  [(0,0),(0,0),(0,0),(0,0)],
  [(0,0),(0,0),(0,0),(0,0)],
  [(0,0),(0,0),(0,0),(0,0)],
  [(0,0),(0,0),(0,0),(0,0)],
  [(0,0),(0,0),(0,0),(0,0)],
  [(0,0),(0,0),(0,0),(0,0)],
  [(0,0),(0,0),(0,0),(0,0)],
  [(0,0),(0,0),(0,0),(0,0)])
R(current_mirror_ota_0, via2, [(4.63,8.72,4.83,8.92), (4.63,8.72,4.83,8.92), (4.63,8.72,4.83,8.92), (9.79,8.72,9.99,8.92), (9.79,8.72,9.99,8.92), (9.79,8.72,9.99,8.92), (9.79,8.72,9.99,8.92), (9.79,8.72,9.99,8.92), (9.79,8.72,9.99,8.92), (9.79,8.72,9.99,8.92), (14.09,8.72,14.29,8.92), (14.09,8.72,14.29,8.92), (14.09,8.72,14.29,8.92), (14.09,8.72,14.29,8.92), (14.09,8.72,14.29,8.92), (14.09,8.72,14.29,8.92), (16.67,8.72,16.87,8.92), (16.67,8.72,16.87,8.92), (16.67,8.72,16.87,8.92), (16.67,8.72,16.87,8.92), (3.77,13.76,3.97,13.96), (3.77,13.76,3.97,13.96), (9.79,13.76,9.99,13.96), (9.79,13.76,9.99,13.96), (14.09,13.76,14.29,13.96), (14.09,13.76,14.29,13.96), (20.11,13.76,20.31,13.96), (20.11,13.76,20.31,13.96), (3.34,17.54,3.54,17.74), (3.34,17.54,3.54,17.74), (3.34,17.54,3.54,17.74), (10.22,17.54,10.42,17.74), (10.22,17.54,10.42,17.74), (10.22,17.54,10.42,17.74), (10.22,17.54,10.42,17.74), (13.66,17.54,13.86,17.74), (13.66,17.54,13.86,17.74), (13.66,17.54,13.86,17.74), (13.66,17.54,13.86,17.74), (13.66,17.54,13.86,17.74), (20.54,17.54,20.74,17.74), (20.54,17.54,20.74,17.74), (1.19,26.36,1.39,26.56), (1.19,26.36,1.39,26.56), (1.19,26.36,1.39,26.56), (1.19,26.36,1.39,26.56), (1.19,26.36,1.39,26.56), (13.23,26.36,13.43,26.56), (13.23,26.36,13.43,26.56), (5.49,31.4,5.69,31.6), (5.49,31.4,5.69,31.6), (11.51,31.4,11.71,31.6)])
A(current_mirror_ota_0, met3, -0.4, -0.4, 4.24, 0.8, 3, 4, 3.44, 8.82)
A(current_mirror_ota_0, met3, 9.92, -0.4, 2.32, 0.8, 1, 4, 0, 8.82)
A(current_mirror_ota_0, met3, 11.44, -0.4, 2.72, 0.8, 1, 4, 0, 8.82)
A(current_mirror_ota_0, met3, 13.36, -0.4, 4.24, 0.8, 1, 4, 0, 8.82)
A(current_mirror_ota_0, met3, 16.8, -0.4, 4.24, 0.8, 1, 4, 0, 8.82)
A(current_mirror_ota_0, met3, 20.24, -0.4, 3.84, 0.8, 1, 4, 0, 8.82)
A(current_mirror_ota_0, met3, 23.28, -0.4, 1.2, 0.8, 1, 4, 0, 8.82)
R(current_mirror_ota_0, met3, [(-0.165,-0.4,0.165,0.4), (23.515,-0.4,23.845,0.4), (4.565,8.42,4.895,9.22), (4.565,8.42,4.895,9.22), (4.565,8.42,4.895,9.22), (9.725,8.42,10.055,9.22), (9.725,8.42,10.055,9.22), (9.725,8.42,10.055,9.22), (9.725,8.42,10.055,9.22), (9.725,8.42,10.055,9.22), (9.725,8.42,10.055,9.22), (9.725,8.42,10.055,9.22), (11.675,8.42,12.005,9.22), (14.025,8.42,14.355,9.22), (14.025,8.42,14.355,9.22), (14.025,8.42,14.355,9.22), (14.025,8.42,14.355,9.22), (14.025,8.42,14.355,9.22), (14.025,8.42,14.355,9.22), (16.605,8.42,16.935,9.22), (16.605,8.42,16.935,9.22), (16.605,8.42,16.935,9.22), (16.605,8.42,16.935,9.22), (3.705,13.46,4.035,14.26), (3.705,13.46,4.035,14.26), (3.87,13.46,9.89,14.26), (9.725,13.46,10.055,14.26), (9.725,13.46,10.055,14.26), (14.025,13.46,14.355,14.26), (14.025,13.46,14.355,14.26), (14.19,13.46,20.21,14.26), (20.045,13.46,20.375,14.26), (20.045,13.46,20.375,14.26), (-0.165,17.24,0.165,18.04), (3.275,17.24,3.605,18.04), (3.275,17.24,3.605,18.04), (3.275,17.24,3.605,18.04), (10.155,17.24,10.485,18.04), (10.155,17.24,10.485,18.04), (10.155,17.24,10.485,18.04), (10.155,17.24,10.485,18.04), (13.595,17.24,13.925,18.04), (13.595,17.24,13.925,18.04), (13.595,17.24,13.925,18.04), (13.595,17.24,13.925,18.04), (13.595,17.24,13.925,18.04), (20.475,17.24,20.805,18.04), (20.475,17.24,20.805,18.04), (23.515,17.24,23.845,18.04), (1.125,26.06,1.455,26.86), (1.125,26.06,1.455,26.86), (1.125,26.06,1.455,26.86), (1.125,26.06,1.455,26.86), (1.125,26.06,1.455,26.86), (11.675,26.06,12.005,26.86), (13.165,26.06,13.495,26.86), (13.165,26.06,13.495,26.86), (5.425,31.1,5.755,31.9), (5.425,31.1,5.755,31.9), (5.59,31.1,11.61,31.9), (11.445,31.1,11.775,31.9)])
R(current_mirror_ota_0, via3, [(-0.1,-0.1,0.1,0.1), (23.58,-0.1,23.78,0.1), (11.74,8.72,11.94,8.92), (-0.1,17.54,0.1,17.74), (23.58,17.54,23.78,17.74), (11.74,26.36,11.94,26.56)])
A(current_mirror_ota_0, met4, -0.59, -0.59, 1.18, 10, 3, 3, 11.84, 8.82)
R(current_mirror_ota_0, met4, [(-0.59,-0.165,0.59,0.165), (23.09,-0.165,24.27,0.165), (11.25,8.655,12.43,8.985), (-0.59,17.475,0.59,17.805), (23.09,17.475,24.27,17.805), (11.25,26.295,12.43,26.625)])
R(current_mirror_ota_0, L104_0, [(-4,-4,29.07,39.03)])
R(current_mirror_ota_0, L235_5, [(0,0,25.07,35.03)])
current_mirror_ota_0.add(gdstk.Reference(dcl_nmos_s_47956387_x2_y, (12.04,13.44), rotation=pi))
current_mirror_ota_0.add(gdstk.Reference(dcl_pmos_s_40212493_x3_y, (16.34,13.44), rotation=pi, x_reflection=True))
current_mirror_ota_0.add(gdstk.Reference(dcl_pmos_s_40212493_x3_y, (7.74,13.44)))
current_mirror_ota_0.add(gdstk.Reference(nmos_s_18635307_x2_y2_17, (12.04,13.44), x_reflection=True))
current_mirror_ota_0.add(gdstk.Reference(pmos_s_18257507_x7_y3_17, (7.74,26.88), rotation=pi))
current_mirror_ota_0.add(gdstk.Reference(pmos_s_18257507_x7_y3_17, (16.34,26.88), x_reflection=True))
current_mirror_ota_0.add(gdstk.Reference(dcl_nmos_10568373_x12_y1, (0,26.88)))
current_mirror_ota_0.add(gdstk.Reference(nmos_4t_40251920_x4_y1_1, (20.64,7.56), rotation=pi))
current_mirror_ota_0.add(gdstk.Reference(nmos_4t_40251920_x4_y1_1, (3.44,7.56), x_reflection=True))
current_mirror_ota_0.add(gdstk.Reference(nmos_4t_8992804_x12_y1_1, (24.08,26.88), rotation=pi, x_reflection=True))
current_mirror_ota_0.add(gdstk.Label('ID', (10.32,7.98), layer=69, texttype=5))
current_mirror_ota_0.add(gdstk.Label('VOUT', (19.78,20.58), layer=69, texttype=5))
current_mirror_ota_0.add(gdstk.Label('VINN', (18.06,2.94), layer=68, texttype=5))
current_mirror_ota_0.add(gdstk.Label('VINP', (6.02,2.94), layer=68, texttype=5))
current_mirror_ota_0.add(gdstk.Label('VSS', (11.84,13.23), layer=71, texttype=5))
current_mirror_ota_0.add(gdstk.Label('VSS', (11.84,13.23), layer=71, texttype=5))
current_mirror_ota_0.add(gdstk.Label('VSS', (11.84,13.23), layer=71, texttype=5))
current_mirror_ota_0.add(gdstk.Label('VSS', (11.84,13.23), layer=71, texttype=5))
current_mirror_ota_0.add(gdstk.Label('VSS', (11.84,13.23), layer=71, texttype=5))
current_mirror_ota_0.add(gdstk.Label('VSS', (1.29,30.03), layer=69, texttype=5))
current_mirror_ota_0.add(gdstk.Label('VSS', (11.84,13.23), layer=71, texttype=5))
current_mirror_ota_0.add(gdstk.Label('VSS', (11.84,13.23), layer=71, texttype=5))
current_mirror_ota_0.add(gdstk.Label('VSS', (11.84,13.23), layer=71, texttype=5))
current_mirror_ota_0.add(gdstk.Label('VSS', (11.84,13.23), layer=71, texttype=5))
current_mirror_ota_0.add(gdstk.Label('VSS', (11.84,13.23), layer=71, texttype=5))
current_mirror_ota_0.add(gdstk.Label('VSS', (11.84,13.23), layer=71, texttype=5))
current_mirror_ota_0.add(gdstk.Label('VSS', (11.84,13.23), layer=71, texttype=5))
current_mirror_ota_0.add(gdstk.Label('VSS', (11.84,13.23), layer=71, texttype=5))
current_mirror_ota_0.add(gdstk.Label('VSS', (11.84,13.23), layer=71, texttype=5))
current_mirror_ota_0.add(gdstk.Label('VSS', (11.84,13.23), layer=71, texttype=5))
current_mirror_ota_0.add(gdstk.Label('VSS', (11.84,13.23), layer=71, texttype=5))
current_mirror_ota_0.add(gdstk.Label('VDD', (23.68,13.23), layer=71, texttype=5))
current_mirror_ota_0.add(gdstk.Label('VDD', (23.68,13.23), layer=71, texttype=5))
current_mirror_ota_0.add(gdstk.Label('VDD', (23.68,13.23), layer=71, texttype=5))
current_mirror_ota_0.add(gdstk.Label('VDD', (23.68,13.23), layer=71, texttype=5))
current_mirror_ota_0.add(gdstk.Label('VDD', (23.68,13.23), layer=71, texttype=5))
current_mirror_ota_0.add(gdstk.Label('VDD', (23.68,13.23), layer=71, texttype=5))
current_mirror_ota_0.add(gdstk.Label('VDD', (23.68,13.23), layer=71, texttype=5))
current_mirror_ota_0.add(gdstk.Label('VDD', (23.68,13.23), layer=71, texttype=5))

lib.write_gds('CURRENT_MIRROR_OTA_0.gds')
